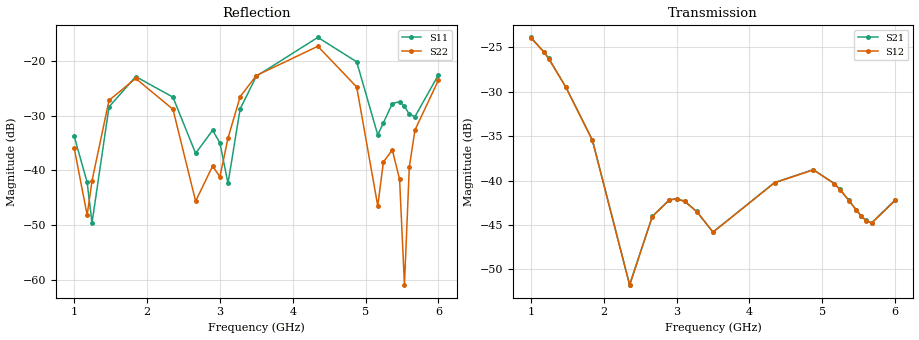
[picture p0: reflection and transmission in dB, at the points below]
!Agilent Technologies,E8364B,MY43040528,A.07.50.67
!Agilent E8364B: A.07.50.67
!Date: Sunday, March 01, 2026 22:36:34
!Correction: S11(Full 2 Port(1,2))
!S21(Full 2 Port(1,2))
!S12(Full 2 Port(1,2))
!S22(Full 2 Port(1,2))
!S2P File: Measurements: S11, S21, S12, S22:
# Hz S  dB  R 50
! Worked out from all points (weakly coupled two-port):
!   451 points, 1 GHz to 6 GHz, reference 50 ohm
!   highest |S21| = -23.87 dB at 1 GHz (marker M1); lowest = -51.7 dB at 2.356 GHz (marker M2)
!   lowest |S11| = -49.6 dB at 1.244 GHz (marker M3), VSWR 1.01, Z = 50.2 - j0.283 ohm
!   |S11| at or under -10 dB: start of sweep to end of sweep
!   |S22| runs from -61.0 to -17.2 dB; largest |S21 - S12| = 0.00026
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1e9  -33.75 14.4  -23.87 155.4  -23.91 155.4  -35.89 -43.2
1.177778e9  -42.17 -0.5  -25.49 54.1  -25.52 54.2  -48.17 -100.7
1.244444e9  -49.59 -58.4  -26.23 16.4  -26.26 16.4  -41.88 -175.0
1.477778e9  -28.37 155.3  -29.43 -112.6  -29.46 -112.6  -27.17 95.7
1.844444e9  -22.82 74.9  -35.44 52.3  -35.47 52.4  -23.16 -5.1
2.355556e9  -26.58 0.3  -51.74 -147.7  -51.79 -147.6  -28.80 -122.4
2.666667e9  -36.87 16.0  -44.05 105.2  -44.07 105.3  -45.61 42.0
2.9e9  -32.64 20.5  -42.17 -15.1  -42.19 -15.1  -39.19 -53.0
3e9  -34.95 8.3  -42.05 -67.6  -42.09 -67.5  -41.16 -34.3
3.111111e9  -42.32 57.7  -42.33 -125.5  -42.36 -125.6  -34.08 -16.2
3.277778e9  -28.75 91.1  -43.49 149.9  -43.52 150.0  -26.51 -50.6
3.5e9  -22.76 55.1  -45.81 48.3  -45.83 48.3  -22.63 -104.6
4.344444e9  -15.65 -47.3  -40.23 26.0  -40.26 26.0  -17.28 103.2
4.877778e9  -20.12 -138.4  -38.77 87.1  -38.81 87.2  -24.73 -28.2
5.166667e9  -33.48 -124.4  -40.34 -84.7  -40.37 -84.7  -46.46 111.4
5.244444e9  -31.28 -97.5  -41.01 -132.4  -41.06 -132.4  -38.44 61.1
5.366667e9  -27.75 -97.5  -42.24 150.1  -42.27 150.1  -36.23 18.0
5.466667e9  -27.41 -107.4  -43.31 83.5  -43.36 83.5  -41.64 -19.5
5.533333e9  -28.28 -109.7  -43.97 37.0  -44.02 37.1  -60.97 -1.1
5.6e9  -29.69 -107.3  -44.49 -10.9  -44.52 -10.9  -39.35 117.2
5.677778e9  -30.14 -92.7  -44.77 -68.5  -44.81 -68.4  -32.59 94.6
6e9  -22.49 -82.6  -42.21 62.9  -42.25 62.9  -23.47 2.9
